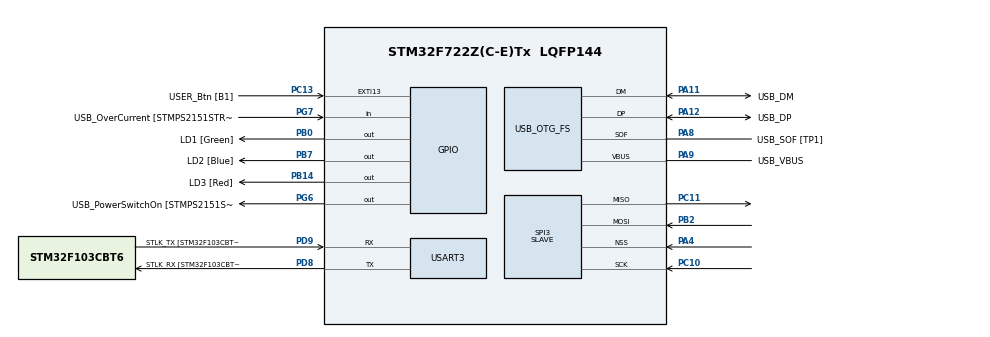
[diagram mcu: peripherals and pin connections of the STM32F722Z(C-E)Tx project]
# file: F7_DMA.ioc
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Dma.Request0=SPI3_RX
Dma.Request1=SPI3_TX
Dma.Request2=USART3_TX
Dma.SPI3_RX.0.Direction=DMA_PERIPH_TO_MEMORY
Dma.SPI3_RX.0.FIFOMode=DMA_FIFOMODE_DISABLE
Dma.SPI3_RX.0.Instance=DMA1_Stream0
Dma.SPI3_RX.0.MemDataAlignment=DMA_MDATAALIGN_BYTE
Dma.SPI3_RX.0.MemInc=DMA_MINC_ENABLE
Dma.SPI3_RX.0.Mode=DMA_NORMAL
Dma.SPI3_RX.0.PeriphDataAlignment=DMA_PDATAALIGN_BYTE
Dma.SPI3_RX.0.PeriphInc=DMA_PINC_DISABLE
Dma.SPI3_RX.0.Priority=DMA_PRIORITY_LOW
Dma.SPI3_TX.1.Direction=DMA_MEMORY_TO_PERIPH
Dma.SPI3_TX.1.FIFOMode=DMA_FIFOMODE_DISABLE
Dma.SPI3_TX.1.Instance=DMA1_Stream5
Dma.SPI3_TX.1.MemDataAlignment=DMA_MDATAALIGN_BYTE
Dma.SPI3_TX.1.MemInc=DMA_MINC_ENABLE
Dma.SPI3_TX.1.Mode=DMA_NORMAL
Dma.SPI3_TX.1.PeriphDataAlignment=DMA_PDATAALIGN_BYTE
Dma.SPI3_TX.1.PeriphInc=DMA_PINC_DISABLE
Dma.SPI3_TX.1.Priority=DMA_PRIORITY_MEDIUM
Dma.USART3_TX.2.Direction=DMA_MEMORY_TO_PERIPH
Dma.USART3_TX.2.FIFOMode=DMA_FIFOMODE_DISABLE
Dma.USART3_TX.2.Instance=DMA1_Stream3
Dma.USART3_TX.2.MemDataAlignment=DMA_MDATAALIGN_BYTE
Dma.USART3_TX.2.MemInc=DMA_MINC_ENABLE
Dma.USART3_TX.2.Mode=DMA_NORMAL
Dma.USART3_TX.2.PeriphDataAlignment=DMA_PDATAALIGN_BYTE
Dma.USART3_TX.2.PeriphInc=DMA_PINC_DISABLE
Dma.USART3_TX.2.Priority=DMA_PRIORITY_LOW
Mcu.Family=STM32F7
Mcu.Name=STM32F722Z(C-E)Tx
Mcu.Package=LQFP144
NVIC.DMA1_Stream0_IRQn=true\:0\:0\:false\:false\:true\:false\:true
NVIC.DMA1_Stream3_IRQn=true\:0\:0\:false\:false\:true\:false\:true
NVIC.DMA1_Stream5_IRQn=true\:0\:0\:false\:false\:true\:false\:true
NVIC.PriorityGroup=NVIC_PRIORITYGROUP_4
NVIC.SPI3_IRQn=true\:0\:0\:false\:false\:true\:true\:true
NVIC.TIM5_IRQn=true\:0\:0\:false\:false\:true\:true\:true
NVIC.USART3_IRQn=true\:0\:0\:false\:false\:true\:true\:true
PA10.GPIO_Label=USB_ID
PA10.Signal=USB_OTG_FS_ID
PA11.GPIO_Label=USB_DM
PA11.Mode=Device_Only
PA11.Signal=USB_OTG_FS_DM
PA12.GPIO_Label=USB_DP
PA12.Mode=Device_Only
PA12.Signal=USB_OTG_FS_DP
PA13.GPIO_Label=TMS
PA13.Mode=Serial_Wire
PA13.Signal=SYS_JTMS-SWDIO
PA14.GPIO_Label=TCK
PA14.Mode=Serial_Wire
PA14.Signal=SYS_JTCK-SWCLK
PA4.Mode=NSS_Signal_Hard_Input
PA4.Signal=SPI3_NSS
PA8.GPIO_Label=USB_SOF [TP1]
PA8.Mode=Activate_SOF_FS
PA8.Signal=USB_OTG_FS_SOF
PA9.GPIO_Label=USB_VBUS
PA9.Mode=Activate_VBUS
PA9.Signal=USB_OTG_FS_VBUS
PB0.GPIO_Label=LD1 [Green]
PB0.Signal=GPIO_Output
PB14.GPIO_Label=LD3 [Red]
PB14.Signal=GPIO_Output
PB2.Mode=Full_Duplex_Slave
PB2.Signal=SPI3_MOSI
PB3.GPIO_Label=SWO
PB3.Signal=SYS_JTDO-SWO
PB7.GPIO_Label=LD2 [Blue]
PB7.Signal=GPIO_Output
PC10.Mode=Full_Duplex_Slave
PC10.Signal=SPI3_SCK
PC11.Mode=Full_Duplex_Slave
PC11.Signal=SPI3_MISO
PC13.GPIO_Label=USER_Btn [B1]
PC13.Signal=GPXTI13
PC14-OSC32_IN.Mode=LSE-External-Oscillator
PC14-OSC32_IN.Signal=RCC_OSC32_IN
PC15-OSC32_OUT.Mode=LSE-External-Oscillator
PC15-OSC32_OUT.Signal=RCC_OSC32_OUT
PD8.GPIO_Label=STLK_RX [STM32F103CBT6_PA3]
PD8.Mode=Asynchronous
PD8.Signal=USART3_TX
PD9.GPIO_Label=STLK_TX [STM32F103CBT6_PA2]
PD9.Mode=Asynchronous
PD9.Signal=USART3_RX
PG6.GPIO_Label=USB_PowerSwitchOn [STMPS2151STR_EN]
PG6.Signal=GPIO_Output
PG7.GPIO_Label=USB_OverCurrent [STMPS2151STR_FAULT]
PG7.Signal=GPIO_Input
PH0-OSC_IN.GPIO_Label=MCO
PH0-OSC_IN.Mode=HSE-External-Clock-Source
PH0-OSC_IN.Signal=RCC_OSC_IN
PH1-OSC_OUT.Mode=HSE-External-Clock-Source
PH1-OSC_OUT.Signal=RCC_OSC_OUT
ProjectManager.HeapSize=0x200
ProjectManager.StackSize=0x400
ProjectManager.TargetToolchain=Makefile
RCC.48MHZClocksFreq_Value=24000000
RCC.AHBFreq_Value=216000000
RCC.APB1CLKDivider=RCC_HCLK_DIV4
RCC.APB1Freq_Value=54000000
RCC.APB1TimFreq_Value=108000000
RCC.APB2CLKDivider=RCC_HCLK_DIV2
RCC.APB2Freq_Value=108000000
RCC.APB2TimFreq_Value=216000000
RCC.CortexFreq_Value=216000000
RCC.HCLKFreq_Value=216000000
RCC.HSE_VALUE=25000000
RCC.HSI_VALUE=16000000
RCC.PLLI2SN=64
RCC.PLLM=25
RCC.PLLMUL=RCC_PLL_MUL9
RCC.PLLN=432
RCC.PLLQ=9
RCC.PLLSAIN=65
RCC.PLLSAIP=RCC_PLLSAIP_DIV8
RCC.PRESCALERUSB=RCC_USBCLKSOURCE_PLL_DIV1_5
RCC.SYSCLKFreq_VALUE=216000000
RCC.SYSCLKSource=RCC_SYSCLKSOURCE_PLLCLK
RCC.SYSCLKSourceVirtual=RCC_SYSCLKSOURCE_PLLCLK
RCC.USART3CLockSelection=RCC_USART3CLKSOURCE_HSI
RCC.USBFreq_Value=48000000
RCC.VCOOutputFreq_Value=432000000
SPI3.DataSize=SPI_DATASIZE_8BIT
SPI3.Direction=SPI_DIRECTION_2LINES
SPI3.Mode=SPI_MODE_SLAVE
SPI3.VirtualNSS=VM_NSSHARD
SPI3.VirtualType=VM_SLAVE
TIM2.AutoReloadPreload=TIM_AUTORELOAD_PRELOAD_DISABLE
TIM2.Prescaler=108-1
TIM5.Period=1000-1
TIM5.Prescaler=108-1
USART3.VirtualMode-Asynchronous=VM_ASYNC
USB_OTG_FS.VirtualMode=Device_Only
VP_TIM2_VS_ClockSourceINT.Mode=Internal
VP_TIM5_VS_ClockSourceINT.Mode=Internal
board=NUCLEO-F722ZE

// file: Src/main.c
/* USER CODE BEGIN Header */
/**
 ******************************************************************************
 * @file           : main.c
 * @brief          : Main program body
 ******************************************************************************
 * @attention
 *
 * <h2><center>&copy; Copyright (c) 2020 STMicroelectronics.
 * All rights reserved.</center></h2>
 *
 * This software component is licensed by ST under BSD 3-Clause license,
 * the "License"; You may not use this file except in compliance with the
 * License. You may obtain a copy of the License at:
 *                        opensource.org/licenses/BSD-3-Clause
 *
 ******************************************************************************
 */
/* USER CODE END Header */
#include "main.h"
#include "dma.h"
#include "spi.h"
#include "tim.h"
#include "usart.h"
#include "usb_otg.h"
#include "gpio.h"

/* USER CODE BEGIN Includes */
#include <stdio.h>
#include <string.h>
#include <string>

/* USER CODE END Includes */

/* USER CODE BEGIN PD */
#define SPI_BUFFER_LENGTH 10

/* USER CODE END PD */

/* USER CODE BEGIN PV */
char _spi_buffer_TX[SPI_BUFFER_LENGTH];
char _char_bufferDMA1[150]; // DMA Buffer
volatile char _spi_buffer_RX[SPI_BUFFER_LENGTH];

uint8_t _spi_rx_flag = 0;
uint8_t _print_tx_flag = 0;
/* USER CODE END PV */

void SystemClock_Config(void);

int main(void)
{

  /* MCU Configuration--------------------------------------------------------*/

  /* Reset of all peripherals, Initializes the Flash interface and the Systick. */
  HAL_Init();

  /* Configure the system clock */
  SystemClock_Config();

  /* Initialize all configured peripherals */
  MX_GPIO_Init();
  MX_DMA_Init();
  MX_SPI3_Init();
  MX_USART3_UART_Init();
  MX_USB_OTG_FS_PCD_Init();
  MX_TIM2_Init();
  MX_TIM5_Init();
  /* USER CODE BEGIN 2 */

    // start timers
    HAL_TIM_Base_Start(&htim2);
    HAL_TIM_Base_Start(&htim5);
    HAL_SPI_Receive_DMA(&hspi3, (uint8_t *)_spi_buffer_RX, SPI_BUFFER_LENGTH);

  /* USER CODE END 2 */

  /* Infinite loop */
  /* USER CODE BEGIN WHILE */
    while (1) {
        static uint32_t timerMicros = 0;
        static uint32_t timerMillis = 0;

        // once every second
        if (__HAL_TIM_GetCounter(&htim5) - timerMillis > 1000) {

            timerMicros = __HAL_TIM_GetCounter(&htim2);
            timerMillis = __HAL_TIM_GetCounter(&htim5);

            // prepare first string
            std::string output = "Timer1: ";
            output.append(std::to_string(timerMicros));
            output.append(", Timer2: ");
            output.append(std::to_string(timerMillis));
            output.append("\r\n");
            strcpy(_char_bufferDMA1, output.data());
            // strcpy(_char_bufferDMA1, "test\r\n");

            print((uint8_t *)_char_bufferDMA1, output.size());
            // HAL_UART_Transmit(&huart3, (uint8_t *)_char_bufferDMA1, strlen(_char_bufferDMA1), 100);
        }
    /* USER CODE END WHILE */

    }
}

void SystemClock_Config(void)
{
  RCC_OscInitTypeDef RCC_OscInitStruct = {0};
  RCC_ClkInitTypeDef RCC_ClkInitStruct = {0};
  RCC_PeriphCLKInitTypeDef PeriphClkInitStruct = {0};

  /** Configure LSE Drive Capability
  */
  HAL_PWR_EnableBkUpAccess();
  /** Configure the main internal regulator output voltage
  */
  __HAL_RCC_PWR_CLK_ENABLE();
  __HAL_PWR_VOLTAGESCALING_CONFIG(PWR_REGULATOR_VOLTAGE_SCALE3);
  /** Initializes the RCC Oscillators according to the specified parameters
  * in the RCC_OscInitTypeDef structure.
  */
  RCC_OscInitStruct.OscillatorType = RCC_OSCILLATORTYPE_HSE;
  RCC_OscInitStruct.HSEState = RCC_HSE_BYPASS;
  RCC_OscInitStruct.PLL.PLLState = RCC_PLL_ON;
  RCC_OscInitStruct.PLL.PLLSource = RCC_PLLSOURCE_HSE;
  RCC_OscInitStruct.PLL.PLLM = 8;
  RCC_OscInitStruct.PLL.PLLN = 96;
  RCC_OscInitStruct.PLL.PLLP = RCC_PLLP_DIV2;
  RCC_OscInitStruct.PLL.PLLQ = 4;
  if (HAL_RCC_OscConfig(&RCC_OscInitStruct) != HAL_OK)
  {
    Error_Handler();
  }
  /** Activate the Over-Drive mode
  */
  if (HAL_PWREx_EnableOverDrive() != HAL_OK)
  {
    Error_Handler();
  }
  /** Initializes the CPU, AHB and APB buses clocks
  */
  RCC_ClkInitStruct.ClockType = RCC_CLOCKTYPE_HCLK|RCC_CLOCKTYPE_SYSCLK
                              |RCC_CLOCKTYPE_PCLK1|RCC_CLOCKTYPE_PCLK2;
  RCC_ClkInitStruct.SYSCLKSource = RCC_SYSCLKSOURCE_PLLCLK;
  RCC_ClkInitStruct.AHBCLKDivider = RCC_SYSCLK_DIV2;
  RCC_ClkInitStruct.APB1CLKDivider = RCC_HCLK_DIV1;
  RCC_ClkInitStruct.APB2CLKDivider = RCC_HCLK_DIV1;

  if (HAL_RCC_ClockConfig(&RCC_ClkInitStruct, FLASH_LATENCY_1) != HAL_OK)
  {
    Error_Handler();
  }
  PeriphClkInitStruct.PeriphClockSelection = RCC_PERIPHCLK_USART3|RCC_PERIPHCLK_CLK48;
  PeriphClkInitStruct.Usart3ClockSelection = RCC_USART3CLKSOURCE_PCLK1;
  PeriphClkInitStruct.Clk48ClockSelection = RCC_CLK48SOURCE_PLL;
  if (HAL_RCCEx_PeriphCLKConfig(&PeriphClkInitStruct) != HAL_OK)
  {
    Error_Handler();
  }
}

/* USER CODE BEGIN 4 */
void print(uint8_t *str, uint16_t size) {
    while (_print_tx_flag == 1) {
    }
    _print_tx_flag = 1;
    HAL_UART_Transmit_DMA(&huart3, str, size);
}
void HAL_UART_TxCpltCallback(UART_HandleTypeDef *huart) {
    if (huart->Instance == huart3.Instance) {
        // toggle pin to show callback is working
        _print_tx_flag = 0;
        HAL_GPIO_TogglePin(LD1_GPIO_Port, LD1_Pin);
    }
}
void HAL_SPI_RxCpltCallback(SPI_HandleTypeDef *hspi) {
    if (hspi->Instance == hspi3.Instance) {
        _spi_rx_flag = 1;
    }
}
void HAL_SPI_TxCpltCallback(SPI_HandleTypeDef *hspi) {
    if (hspi->Instance == hspi3.Instance) {
        // toggle pin to show callback is working
        HAL_GPIO_TogglePin(LD2_GPIO_Port, LD2_Pin);
    }
}
/* USER CODE END 4 */

void Error_Handler(void)
{
}

/************************ (C) COPYRIGHT STMicroelectronics *****END OF FILE****/
